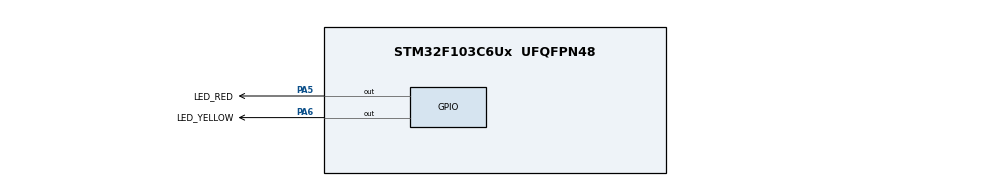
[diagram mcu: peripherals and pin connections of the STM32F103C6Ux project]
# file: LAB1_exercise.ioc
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Mcu.Family=STM32F1
Mcu.Name=STM32F103C6Ux
Mcu.Package=UFQFPN48
NVIC.PriorityGroup=NVIC_PRIORITYGROUP_4
PA5.GPIO_Label=LED_RED
PA5.PinState=GPIO_PIN_RESET
PA5.Signal=GPIO_Output
PA6.GPIO_Label=LED_YELLOW
PA6.PinState=GPIO_PIN_SET
PA6.Signal=GPIO_Output
ProjectManager.HeapSize=0x200
ProjectManager.StackSize=0x400
ProjectManager.TargetToolchain=STM32CubeIDE
RCC.APB1Freq_Value=8000000
RCC.APB2Freq_Value=8000000
VP_SYS_VS_ND.Mode=No_Debug
board=custom

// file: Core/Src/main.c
/* USER CODE BEGIN Header */
/**
  ******************************************************************************
  * @file           : main.c
  * @brief          : Main program body
  ******************************************************************************
  * @attention
  *
  * <h2><center>&copy; Copyright (c) 2023 STMicroelectronics.
  * All rights reserved.</center></h2>
  *
  * This software component is licensed by ST under BSD 3-Clause license,
  * the "License"; You may not use this file except in compliance with the
  * License. You may obtain a copy of the License at:
  *                        opensource.org/licenses/BSD-3-Clause
  *
  ******************************************************************************
  */
/* USER CODE END Header */
#include "main.h"

void SystemClock_Config(void);
static void MX_GPIO_Init(void);

/* USER CODE BEGIN 0 */
void clearALLClock(){
	HAL_GPIO_WritePin(LED0_GPIO_Port, LED0_Pin, SET);
	HAL_GPIO_WritePin(LED1_GPIO_Port, LED1_Pin, SET);
	HAL_GPIO_WritePin(LED2_GPIO_Port, LED2_Pin, SET);
	HAL_GPIO_WritePin(LED3_GPIO_Port, LED3_Pin, SET);
	HAL_GPIO_WritePin(LED4_GPIO_Port, LED4_Pin, SET);
	HAL_GPIO_WritePin(LED5_GPIO_Port, LED5_Pin, SET);
	HAL_GPIO_WritePin(LED6_GPIO_Port, LED6_Pin, SET);
	HAL_GPIO_WritePin(LED7_GPIO_Port, LED7_Pin, SET);
	HAL_GPIO_WritePin(LED8_GPIO_Port, LED8_Pin, SET);
	HAL_GPIO_WritePin(LED9_GPIO_Port, LED9_Pin, SET);
	HAL_GPIO_WritePin(LED10_GPIO_Port, LED10_Pin, SET);
	HAL_GPIO_WritePin(LED11_GPIO_Port, LED11_Pin, SET);

}

void setNumberOnClock(int num){
	if (num==0) HAL_GPIO_WritePin(LED0_GPIO_Port, LED0_Pin, RESET);
	else if (num==1) HAL_GPIO_WritePin(LED1_GPIO_Port, LED1_Pin, RESET);
	else if (num==2) HAL_GPIO_WritePin(LED2_GPIO_Port, LED2_Pin, RESET);
	else if (num==3) HAL_GPIO_WritePin(LED3_GPIO_Port, LED3_Pin, RESET);
	else if (num==4) HAL_GPIO_WritePin(LED4_GPIO_Port, LED4_Pin, RESET);
	else if (num==5) HAL_GPIO_WritePin(LED5_GPIO_Port, LED5_Pin, RESET);
	else if (num==6) HAL_GPIO_WritePin(LED6_GPIO_Port, LED6_Pin, RESET);
	else if (num==7) HAL_GPIO_WritePin(LED7_GPIO_Port, LED7_Pin, RESET);
	else if (num==8) HAL_GPIO_WritePin(LED8_GPIO_Port, LED8_Pin, RESET);
	else if (num==9) HAL_GPIO_WritePin(LED9_GPIO_Port, LED9_Pin, RESET);
	else if (num==10) HAL_GPIO_WritePin(LED10_GPIO_Port, LED10_Pin, RESET);
	else if (num==11) HAL_GPIO_WritePin(LED11_GPIO_Port, LED11_Pin, RESET);
}
void clearNumberOnClock(int num){
	if (num==0) HAL_GPIO_WritePin(LED0_GPIO_Port, LED0_Pin, SET);
	else if (num==1) HAL_GPIO_WritePin(LED1_GPIO_Port, LED1_Pin, SET);
	else if (num==2) HAL_GPIO_WritePin(LED2_GPIO_Port, LED2_Pin, SET);
	else if (num==3) HAL_GPIO_WritePin(LED3_GPIO_Port, LED3_Pin, SET);
	else if (num==4) HAL_GPIO_WritePin(LED4_GPIO_Port, LED4_Pin, SET);
	else if (num==5) HAL_GPIO_WritePin(LED5_GPIO_Port, LED5_Pin, SET);
	else if (num==6) HAL_GPIO_WritePin(LED6_GPIO_Port, LED6_Pin, SET);
	else if (num==7) HAL_GPIO_WritePin(LED7_GPIO_Port, LED7_Pin, SET);
	else if (num==8) HAL_GPIO_WritePin(LED8_GPIO_Port, LED8_Pin, SET);
	else if (num==9) HAL_GPIO_WritePin(LED9_GPIO_Port, LED9_Pin, SET);
	else if (num==10) HAL_GPIO_WritePin(LED10_GPIO_Port, LED10_Pin, SET);
	else if (num==11) HAL_GPIO_WritePin(LED11_GPIO_Port, LED11_Pin, SET);
}
/* USER CODE END 0 */

int main(void)
{

  /* MCU Configuration--------------------------------------------------------*/

  /* Reset of all peripherals, Initializes the Flash interface and the Systick. */
  HAL_Init();

  /* Configure the system clock */
  SystemClock_Config();

  /* Initialize all configured peripherals */
  MX_GPIO_Init();
  /* USER CODE BEGIN 2 */
  int sec_counter=0;
  int min_counter=0;
  int hr_counter=0;

  /* USER CODE END 2 */

  /* Infinite loop */
  /* USER CODE BEGIN WHILE */
  while (1)
  {
	  if (sec_counter == 60){
		  sec_counter=0;
		  min_counter++;
	  }
	  if (min_counter == 60){
		  min_counter=0;
		  hr_counter++;
	  }
	  if (hr_counter == 12){
		  hr_counter=0;
	  }
	  clearALLClock();
	  setNumberOnClock(sec_counter/5);
	  setNumberOnClock(min_counter/5);
	  setNumberOnClock(hr_counter%12);
	  sec_counter++;
	  HAL_Delay(10);
    /* USER CODE END WHILE */

  }
}

void SystemClock_Config(void)
{
  RCC_OscInitTypeDef RCC_OscInitStruct = {0};
  RCC_ClkInitTypeDef RCC_ClkInitStruct = {0};

  /** Initializes the RCC Oscillators according to the specified parameters
  * in the RCC_OscInitTypeDef structure.
  */
  RCC_OscInitStruct.OscillatorType = RCC_OSCILLATORTYPE_HSI;
  RCC_OscInitStruct.HSIState = RCC_HSI_ON;
  RCC_OscInitStruct.HSICalibrationValue = RCC_HSICALIBRATION_DEFAULT;
  RCC_OscInitStruct.PLL.PLLState = RCC_PLL_NONE;
  if (HAL_RCC_OscConfig(&RCC_OscInitStruct) != HAL_OK)
  {
    Error_Handler();
  }
  /** Initializes the CPU, AHB and APB buses clocks
  */
  RCC_ClkInitStruct.ClockType = RCC_CLOCKTYPE_HCLK|RCC_CLOCKTYPE_SYSCLK
                              |RCC_CLOCKTYPE_PCLK1|RCC_CLOCKTYPE_PCLK2;
  RCC_ClkInitStruct.SYSCLKSource = RCC_SYSCLKSOURCE_HSI;
  RCC_ClkInitStruct.AHBCLKDivider = RCC_SYSCLK_DIV1;
  RCC_ClkInitStruct.APB1CLKDivider = RCC_HCLK_DIV1;
  RCC_ClkInitStruct.APB2CLKDivider = RCC_HCLK_DIV1;

  if (HAL_RCC_ClockConfig(&RCC_ClkInitStruct, FLASH_LATENCY_0) != HAL_OK)
  {
    Error_Handler();
  }
}

static void MX_GPIO_Init(void)
{
  GPIO_InitTypeDef GPIO_InitStruct = {0};

  /* GPIO Ports Clock Enable */
  __HAL_RCC_GPIOA_CLK_ENABLE();

  /*Configure GPIO pin Output Level */
  HAL_GPIO_WritePin(LED0_GPIO_Port, LED0_Pin, GPIO_PIN_RESET);

  /*Configure GPIO pin Output Level */
  HAL_GPIO_WritePin(GPIOA, LED1_Pin|LED2_Pin|LED3_Pin|LED4_Pin
                          |LED5_Pin|LED6_Pin|LED7_Pin|LED8_Pin
                          |LED9_Pin|LED10_Pin|LED11_Pin, GPIO_PIN_SET);

  /*Configure GPIO pins : LED0_Pin LED1_Pin LED2_Pin LED3_Pin
                           LED4_Pin LED5_Pin LED6_Pin LED7_Pin
                           LED8_Pin LED9_Pin LED10_Pin LED11_Pin */
  GPIO_InitStruct.Pin = LED0_Pin|LED1_Pin|LED2_Pin|LED3_Pin
                          |LED4_Pin|LED5_Pin|LED6_Pin|LED7_Pin
                          |LED8_Pin|LED9_Pin|LED10_Pin|LED11_Pin;
  GPIO_InitStruct.Mode = GPIO_MODE_OUTPUT_PP;
  GPIO_InitStruct.Pull = GPIO_NOPULL;
  GPIO_InitStruct.Speed = GPIO_SPEED_FREQ_LOW;
  HAL_GPIO_Init(GPIOA, &GPIO_InitStruct);

}

void Error_Handler(void)
{
  __disable_irq();
  while (1)
  {
  }
}

/************************ (C) COPYRIGHT STMicroelectronics *****END OF FILE****/
